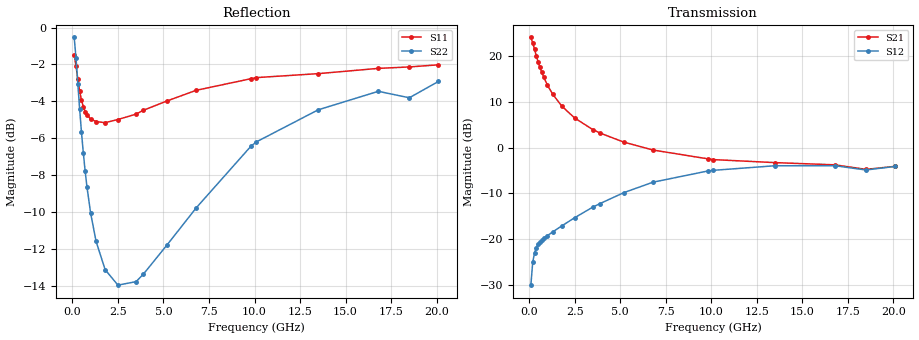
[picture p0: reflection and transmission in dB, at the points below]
!  Infineon Technologies AG
! BFR380L3 , PF131585-7, No.6, Th 09.10.01, soldered on pcb-board, measured with PP GSG850
!  Vce=1.5 V,  Ic=5.0 mA
! Common Emitter S-Parameters:  15. November 2001
#  GHz  S  MA  R  50
! f  S11  S21  S12  S22
! GHz  Mag  Ang  Mag  Ang  Mag  Ang  Mag  Ang
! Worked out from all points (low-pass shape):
!   201 points, 100 MHz to 20.1 GHz, reference 50 ohm
!   highest |S21| = 23.97 dB at 100 MHz (marker M1); lowest = -4.8 dB at 18.5 GHz (marker M2)
!   |S21| within 3 dB of the highest: start of sweep to 328.2 MHz
!   lowest |S11| = -5.2 dB at 1.8 GHz (marker M3), VSWR 3.46, Z = 14.4 - j0.076 ohm
!   |S11| at or under -10 dB: nowhere
!   |S22| runs from -14.1 to -0.5 dB; largest |S21 - S12| = 16
!   S11 on the Smith chart (normalised r, x): 100 MHz: 1.12, -3.31; 400 MHz: 0.34, -0.82; 1 GHz: 0.30, -0.24; 3.9 GHz: 0.28, +0.34; 9.8 GHz: 0.38, +1.14; 20.1 GHz: 0.97, +2.56
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0.1  0.8429 -30.6  15.79 159.8  0.03179 73.0  0.9403 -19.5
0.2  0.787 -58.1  13.75 143.0  0.05614 60.9  0.8247 -35.6
0.3  0.7231 -79.9  11.7 130.2  0.07122 52.5  0.7032 -47.6
0.4  0.6711 -97.0  9.946 120.5  0.08147 47.1  0.6001 -56.4
0.5  0.6354 -110.6  8.541 113.0  0.08841 43.9  0.5196 -63.0
0.6  0.61 -121.6  7.428 107.2  0.09413 41.9  0.4575 -68.2
0.7  0.5917 -130.8  6.562 102.2  0.09839 40.7  0.4083 -72.4
0.8  0.5798 -138.3  5.856 98.0  0.1023 40.3  0.3698 -76.0
1  0.5648 -150.5  4.817 91.1  0.1097 40.4  0.3143 -81.8
1.3  0.5558 -163.9  3.796 82.9  0.1206 41.8  0.263 -89.0
1.8  0.552 -179.8  2.819 71.9  0.1403 44.6  0.2203 -98.9
2.5  0.563 163.9  2.097 59.3  0.1719 47.3  0.2001 -112.3
3.5  0.5823 145.9  1.566 44.3  0.2245 48.2  0.2045 -130.5
3.9  0.5965 139.9  1.436 39.2  0.2455 47.7  0.2143 -139.0
5.2  0.6323 122.7  1.145 24.2  0.3225 42.7  0.2573 -160.8
6.8  0.6757 104.2  0.9391 10.2  0.4189 34.2  0.3242 172.5
9.799999  0.7263 79.2  0.7536 -6.8  0.5543 14.2  0.4763 135.1
10.1  0.7314 77.4  0.7388 -8.0  0.5639 12.2  0.4895 131.8
13.5  0.7498 59.1  0.6847 -21.9  0.6331 -9.8  0.5982 100.1
16.8  0.7748 47.4  0.6477 -33.2  0.6332 -26.1  0.6714 77.4
18.5  0.7818 45.5  0.578 -40.4  0.5691 -34.6  0.6448 71.6
20.1  0.7923 38.2  0.6237 -44.0  0.6222 -39.7  0.7141 60.7
